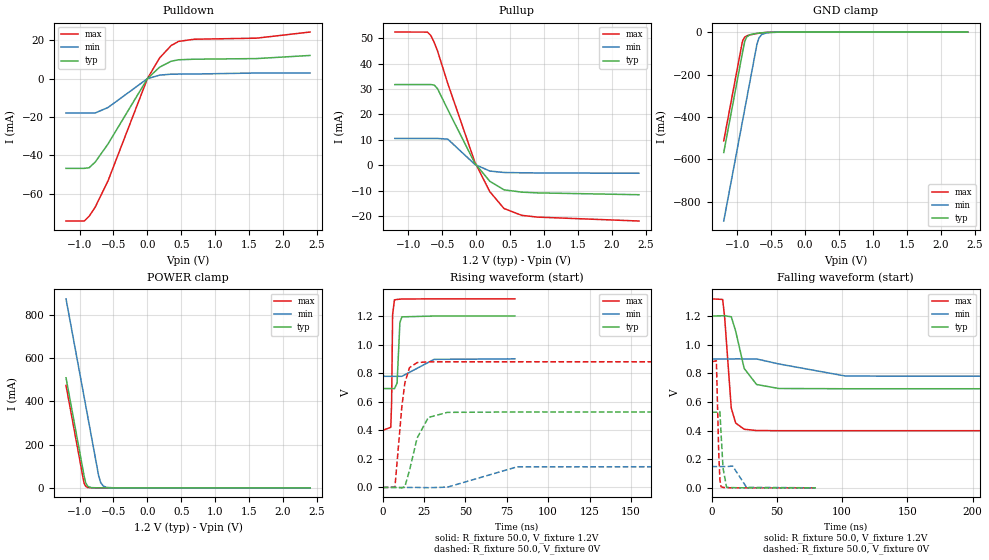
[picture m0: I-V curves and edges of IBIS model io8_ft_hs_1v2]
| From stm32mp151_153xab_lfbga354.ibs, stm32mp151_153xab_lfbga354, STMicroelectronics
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[Model]   io8_ft_hs_1v2
Model_type I/O
Polarity   Non-Inverting
Enable   Active-Low
| CAP_THRESHOLD on pad IOFT is "UDTCAPC" :
| Rising=20.00f vddiom   Falling=80.00f vddiom
| C_comp min and max val. don't necessarily correlate with the min and max pvt
| but are the smallest and greatest pad capacitance found.
| var   typ   min   max
C_comp   3.10955pF  3.08200pF  3.12755pF
|C_comp_pullup   1.83575pF  1.59880pF  1.76540pF
|C_comp_pulldown   1.27380pF  1.48320pF  1.36215pF
Vinl = 360.0mV
Vinh = 792.0mV
Vmeas = 600.0mV   | Reference voltage for timing measurements
Cref  = 50.0pF   | Timing specification test load capacitance value
Rref  = 100.0MOhm   | Timing specification test load resistance value
Vref  = 0V   | Timing specification test load voltage
[Model Spec]
| TIME_THRESHOLD on pin ZIV11 is "CMOS" :
| Rising=40.00f vdd   Falling=60.00f vdd
Vinl 463.60000mV 362.60000mV 506.60000mV
Vinh 741.40000mV 545.40000mV 817.40000mV
| variable   typ   min   max
[Temperature Range] 25.0 140.0 -40.0
| variable   typ   min   max
[Voltage Range] 1.2V 900.0mV 1.32V
| variable   typ   min   max
[POWER Clamp Reference] 1.2V 900.0mV 1.32V
| variable   typ   min   max
[GND Clamp Reference] 0V 0V 0V
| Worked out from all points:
|   slope of the pulldown table from 0 to 0.18 V, typ, clamps not added: 30 ohm
|   slope of the pullup table from 0 to 0.18 V, typ, clamps not added: 31.1 ohm
|   GND clamp passes 1 mA (typ) near -0.52 V on its own axis
|   POWER clamp passes 1 mA (typ) near -0.83 V on its own axis
|   rising waveform, R_fixture 50.0, V_fixture 1.2V: 20-80 % time 986ps typ, 2.99ns min, 510ps max; typ from 0.692 V to 1.2 V
|   falling waveform, R_fixture 50.0, V_fixture 1.2V: 20-80 % time 8.61ns typ, 22.8ns min, 4.22ns max; typ from 1.2 V to 0.692 V
|   rising waveform, R_fixture 50.0, V_fixture 0V: 20-80 % time 7.36ns typ, 17.7ns min, 4.07ns max; typ from 0 V to 0.528 V
|   falling waveform, R_fixture 50.0, V_fixture 0V: 20-80 % time 2.15ns typ, 4.88ns min, 1.52ns max; typ from 0.528 V to 0 V
[POWER Clamp]
-1.2V     508.8mA    874.1mA    473.5mA
-940mV    66.83mA    432.1mA    31.5mA
-930mV    49.83mA    415.1mA    19.15mA
-910mV    22.88mA    381.1mA    7.077mA
-880mV    7.117mA    330.1mA    1.59mA
-830mV    1.017mA    245.1mA    132uA
-720mV    14.05uA    58.12mA    554nA
-690mV    4.373uA    25.03mA    124.7nA
-650mV    922.4nA    8.136mA    17.22nA
-600mV    132.5nA    1.998mA    1.555nA
-490mV    2.763nA    90.9uA     103.5pA
2.4V      0A         0A         0A
[GND Clamp]
-1.2V     -567.2mA   -889.7mA   -512.2mA
-930mV    -108.2mA   -430.7mA   -53.23mA
-920mV    -91.21mA   -413.7mA   -40.49mA
-890mV    -43.51mA   -362.7mA   -23.59mA
-860mV    -22.57mA   -311.7mA   -17.89mA
-810mV    -12.11mA   -226.7mA   -13.23mA
-710mV    -6.053mA   -57.05mA   -7.064mA
-680mV    -4.908mA   -27.37mA   -5.632mA
-640mV    -3.605mA   -11.51mA   -3.985mA
-560mV    -1.665mA   -3.218mA   -1.61mA
-360mV    -34.72uA   -209.4uA   -9.248uA
2.4V      3.381nA    1.198uA    162.5pA
| variable   typ   min   max
[Pullup Reference] 1.2V 900.0mV 1.32V
| variable   typ   min   max
[Pulldown Reference] 0V 0V 0V
[Pullup]
-1.2V     31.77mA    10.56mA    52.45mA
-720mV    31.77mA    10.56mA    52.43mA
-670mV    31.77mA    10.56mA    51.08mA
-620mV    31.6mA     10.56mA    48.4mA
-570mV    30.11mA    10.56mA    44.93mA
-420mV    21.94mA    10.3mA     32.23mA
-20mV     787.9uA    340.3uA    1.238mA
200mV     -6.284mA   -2.265mA   -10.37mA
410mV     -9.651mA   -2.83mA    -17.01mA
670mV     -10.56mA   -2.945mA   -19.69mA
900mV     -10.86mA   -3.008mA   -20.39mA
2.4V      -11.58mA   -3.134mA   -21.93mA
[Pulldown]
-1.2V     -46.7mA    -17.86mA   -74.13mA
-930mV    -46.7mA    -17.86mA   -74.13mA
-860mV    -46.38mA   -17.86mA   -71.67mA
-770mV    -43.45mA   -17.86mA   -66.94mA
-580mV    -33.98mA   -14.99mA   -53.18mA
0V        0A         0A         0A
180mV     6.001mA    1.854mA    10.79mA
350mV     9.086mA    2.357mA    17.24mA
460mV     9.857mA    2.4mA      19.42mA
690mV     10.15mA    2.431mA    20.56mA
1.61V     10.48mA    2.965mA    21.11mA
2.4V      12.11mA    2.965mA    24.31mA
[Ramp]
dV/dt_r 316.99135mV/7.36155ns 89.07848mV/17.68703ns 527.83651mV/4.07371ns
dV/dt_f 304.65901mV/8.60631ns 73.19211mV/22.84083ns 552.4109mV/4.21755ns
R_load = 50.0
| Removed startup time: 0s 0s 0s  .
| Removed end time: 79.9ns.
[Rising Waveform]
R_fixture   = 50.0
V_fixture   = 1.2V
V_fixture_min = 900.0mV
V_fixture_max = 1.32V
0s        692.2mV    778mV      399.3mV
4.9ns     692.2mV    778mV      421.3mV
5.4ns     692.2mV    778mV      597.7mV
6ns       692.3mV    778mV      1.209V
7.1ns     691.4mV    778mV      1.313V
8.7ns     730.5mV    778mV      1.316V
10.4ns    1.154V     778mV      1.318V
11.6ns    1.194V     778mV      1.319V
31.1ns    1.2V       896.5mV    1.32V
79.9ns    1.2V       900mV      1.32V
| Removed startup time: 0s 0s 0s  .
| Removed end time: 399.9ns.
[Falling Waveform]
R_fixture   = 50.0
V_fixture   = 1.2V
V_fixture_min = 900.0mV
V_fixture_max = 1.32V
0s        1.2V       900mV      1.32V
8.5ns     1.202V     900mV      1.316V
10ns      1.202V     900mV      1.196V
15.1ns    1.195V     899.9mV    557.4mV
18.5ns    1.094V     900.9mV    452.4mV
25ns      833.9mV    900.5mV    409.2mV
34.5ns    721.8mV    900.3mV    400.3mV
51.6ns    694mV      865.3mV    399.3mV
102.8ns   692.2mV    780.7mV    399.3mV
399.9ns   692.2mV    778mV      399.3mV
| Removed startup time: 0s 0s 0s  .
| Removed end time: 399.9ns.
[Rising Waveform]
R_fixture   = 50.0
V_fixture   = 0V
V_fixture_min = 0V
V_fixture_max = 0V
0s        50.36nV    1.017uV    135.6nV
7.4ns     94.81uV    1.097uV    2.269mV
11.6ns    -2.749mV   1.095uV    567.9mV
13.4ns    4.819mV    1.094uV    731.4mV
16.2ns    119.7mV    777nV      838.9mV
20.8ns    345.7mV    38.44uV    874.1mV
27.6ns    489.7mV    -1.68mV    879.3mV
39.1ns    525.6mV    2.046mV    879.6mV
81.1ns    528.2mV    143.9mV    879.7mV
399.9ns   528.3mV    148.5mV    879.7mV
| Removed startup time: 0s 0s 0s  .
| Removed end time: 79.9ns.
[Falling Waveform]
R_fixture   = 50.0
V_fixture   = 0V
V_fixture_min = 0V
V_fixture_max = 0V
0s        528.3mV    148.5mV    879.7mV
3.7ns     528.3mV    148.5mV    888mV
5.5ns     529mV      148.5mV    243.5mV
6.4ns     532.7mV    148.5mV    57.34mV
7.2ns     393.4mV    148.5mV    8.398mV
8.8ns     138.8mV    148.5mV    3.209mV
11.5ns    4.073mV    148.5mV    1.141mV
16.2ns    1.329mV    152mV      284.6uV
26.8ns    208.4uV    3.678mV    17.1uV
79.9ns    326.9nV    43.68uV    871.7nV
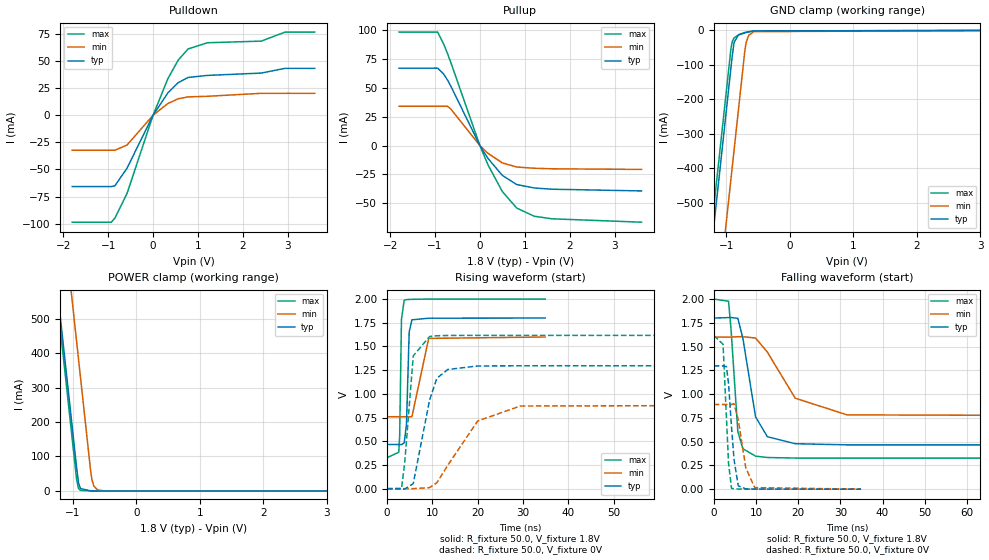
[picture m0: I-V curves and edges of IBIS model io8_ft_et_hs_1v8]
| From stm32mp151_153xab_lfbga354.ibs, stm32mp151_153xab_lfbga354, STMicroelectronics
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[Model]   io8_ft_et_hs_1v8
Model_type I/O
Polarity   Non-Inverting
Enable   Active-Low
| CAP_THRESHOLD on pad IOFT is "UDTCAPC" :
| Rising=20.00f vddiom   Falling=80.00f vddiom
| C_comp min and max val. don't necessarily correlate with the min and max pvt
| but are the smallest and greatest pad capacitance found.
| var   typ   min   max
C_comp   3.43098pF  3.42356pF  3.49925pF
|C_comp_pullup   1.96705pF  2.05925pF  1.91835pF
|C_comp_pulldown   1.46393pF  1.36431pF  1.58090pF
Vinl = 640.0mV
Vinh = 1.2V
Vmeas = 900.0mV   | Reference voltage for timing measurements
Cref  = 50.0pF   | Timing specification test load capacitance value
Rref  = 100.0MOhm   | Timing specification test load resistance value
Vref  = 0V   | Timing specification test load voltage
[Model Spec]
| TIME_THRESHOLD on pin ZIV11 is "CMOS" :
| Rising=40.00f vdd   Falling=60.00f vdd
Vinl 738.60000mV 665.60000mV 824.60000mV
Vinh 1.04640V 924.40000mV 1.13940V
| variable   typ   min   max
[Temperature Range] 25.0 140.0 -40.0
| variable   typ   min   max
[Voltage Range] 1.8V 1.6V 2.0V
| variable   typ   min   max
[POWER Clamp Reference] 1.8V 1.6V 2.0V
| variable   typ   min   max
[GND Clamp Reference] 0V 0V 0V
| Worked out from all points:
|   slope of the pulldown table from 0 to 0.27 V, typ, clamps not added: 16 ohm
|   slope of the pullup table from 0 to 0.27 V, typ, clamps not added: 17 ohm
|   GND clamp passes 1 mA (typ) near -0.52 V on its own axis
|   POWER clamp passes 1 mA (typ) near -0.83 V on its own axis
|   rising waveform, R_fixture 50.0, V_fixture 1.8V: 20-80 % time 437ps typ, 906ps min, 301ps max; typ from 0.466 V to 1.8 V
|   falling waveform, R_fixture 50.0, V_fixture 1.8V: 20-80 % time 2.94ns typ, 7.3ns min, 1.46ns max; typ from 1.8 V to 0.466 V
|   rising waveform, R_fixture 50.0, V_fixture 0V: 20-80 % time 3.11ns typ, 7.36ns min, 1.52ns max; typ from 0 V to 1.3 V
|   falling waveform, R_fixture 50.0, V_fixture 0V: 20-80 % time 1.32ns typ, 2.03ns min, 920ps max; typ from 1.3 V to 0 V
[POWER Clamp]
-1.8V     1.529A     1.894A     1.494A
-940mV    66.83mA    432.1mA    31.5mA
-910mV    22.88mA    381.1mA    7.077mA
-880mV    7.117mA    330.1mA    1.59mA
-720mV    14.05uA    58.12mA    554nA
-700mV    6.453uA    33.14mA    205nA
-670mV    2.008uA    14.27mA    46.29nA
-610mV    195.5nA    2.645mA    2.508nA
-500mV    3.962nA    120.4uA    139.7pA
3.6V      0A         0A         0A
[GND Clamp]
-1.8V     -1.588A    -1.91A     -1.533A
-1.26V    -670.3mA   -992.4mA   -614.9mA
-1.2V     -568.3mA   -890.4mA   -512.9mA
-930mV    -109.3mA   -431.4mA   -53.86mA
-910mV    -75.33mA   -397.4mA   -32.91mA
-880mV    -34.88mA   -346.4mA   -21.56mA
-810mV    -12.56mA   -227.4mA   -13.55mA
-710mV    -6.275mA   -57.63mA   -7.234mA
-690mV    -5.461mA   -35.21mA   -6.234mA
-650mV    -4.039mA   -14.43mA   -4.463mA
-570mV    -1.908mA   -3.832mA   -1.869mA
3.6V      5.084nA    1.599uA    245.6pA
| variable   typ   min   max
[Pullup Reference] 1.8V 1.6V 2.0V
| variable   typ   min   max
[Pulldown Reference] 0V 0V 0V
[Pullup]
-1.8V     67.02mA    34.03mA    98.24mA
-940mV    67.02mA    34.03mA    98.24mA
-810mV    62.07mA    34.03mA    88.1mA
-720mV    56.66mA    34.03mA    79.54mA
-650mV    51.66mA    31.79mA    72.23mA
0V        7.41pA     1.33nA     4.294pA
180mV     -11.09mA   -6.716mA   -16.63mA
500mV     -25.8mA    -15mA      -39.78mA
820mV     -33.72mA   -18.55mA   -54.08mA
1.21V     -36.68mA   -19.61mA   -61.13mA
1.6V      -37.75mA   -20.08mA   -63.35mA
3.6V      -39.24mA   -20.63mA   -66.3mA
[Pulldown]
-1.8V     -65.8mA    -32.31mA   -98.64mA
-930mV    -65.8mA    -32.31mA   -98.64mA
-850mV    -65.04mA   -32.31mA   -94.81mA
-580mV    -48.83mA   -27.49mA   -72.14mA
0V        0A         -3pA       0A
330mV     20.59mA    10.79mA    33.74mA
560mV     30.02mA    15.15mA    50.81mA
780mV     34.81mA    16.9mA     61.1mA
1.21V     36.69mA    17.44mA    66.81mA
2.41V     38.85mA    20.19mA    68.31mA
2.94V     43.21mA    20.19mA    76.64mA
3.6V      43.21mA    20.19mA    76.64mA
[Ramp]
dV/dt_r 777.93018mV/3.10442ns 534.23292mV/7.35934ns 970.1258mV/1.52263ns
dV/dt_f 800.59875mV/2.93456ns 504.72162mV/7.29661ns 1.00395V/1.45577ns
R_load = 50.0
| Removed startup time: 0s 0s 0s  .
| Removed end time: 34.9ns.
[Rising Waveform]
R_fixture   = 50.0
V_fixture   = 1.8V
V_fixture_min = 1.6V
V_fixture_max = 2.0V
0s        465.7mV    758.8mV    326.8mV
2.6ns     465.7mV    758.8mV    384.2mV
2.8ns     465.7mV    758.8mV    552.8mV
3.2ns     464.9mV    758.8mV    1.785V
3.8ns     482.2mV    758.8mV    1.989V
4.3ns     676.5mV    758.8mV    1.994V
4.9ns     1.653V     758.9mV    1.996V
5.5ns     1.781V     758.3mV    1.997V
9.2ns     1.798V     1.585V     2V
34.9ns    1.8V       1.6V       2V
| Removed startup time: 0s 0s 0s  .
| Removed end time: 199.9ns.
[Falling Waveform]
R_fixture   = 50.0
V_fixture   = 1.8V
V_fixture_min = 1.6V
V_fixture_max = 2.0V
0s        1.8V       1.6V       2V
3.5ns     1.805V     1.6V       1.977V
4.1ns     1.806V     1.6V       1.676V
5.7ns     1.797V     1.604V     606.9mV
6.9ns     1.587V     1.604V     425mV
9.9ns     761.1mV    1.59V      347.6mV
12.7ns    551.8mV    1.442V     333.1mV
19.3ns    478.2mV    956.9mV    327.3mV
31.6ns    466.1mV    781.7mV    326.8mV
199.9ns   465.7mV    758.8mV    326.8mV
| Removed startup time: 0s 0s 0s  .
| Removed end time: 199.9ns.
[Rising Waveform]
R_fixture   = 50.0
V_fixture   = 0V
V_fixture_min = 0V
V_fixture_max = 0V
0s        626.1nV    548.5nV    -418.8nV
3.2ns     194.9uV    667.5nV    1.079mV
3.9ns     -5.268mV   816.8nV    266.4mV
5.8ns     53.91mV    103.4uV    1.401V
9.4ns     935.7mV    10.76mV    1.605V
11ns      1.164V     62.56mV    1.613V
13.4ns    1.257V     246.3mV    1.616V
20ns      1.294V     713.8mV    1.617V
29.4ns    1.296V     871.9mV    1.617V
199.9ns   1.297V     890.4mV    1.617V
| Removed startup time: 0s 0s 0s  .
| Removed end time: 34.9ns.
[Falling Waveform]
R_fixture   = 50.0
V_fixture   = 0V
V_fixture_min = 0V
V_fixture_max = 0V
0s        1.297V     890.4mV    1.617V
2.2ns     1.297V     890.4mV    1.524V
3ns       1.29V      890.4mV    755mV
3.5ns     1.109V     890.5mV    272.6mV
4.2ns     655.1mV    890.2mV    9.557mV
4.8ns     312mV      899.7mV    3.295mV
5.8ns     35.07mV    730.6mV    1.496mV
7.6ns     2.478mV    222mV      713.6uV
9.7ns     1.069mV    16.4mV     328uV
34.9ns    -58.81nV   40.43uV    -141nV
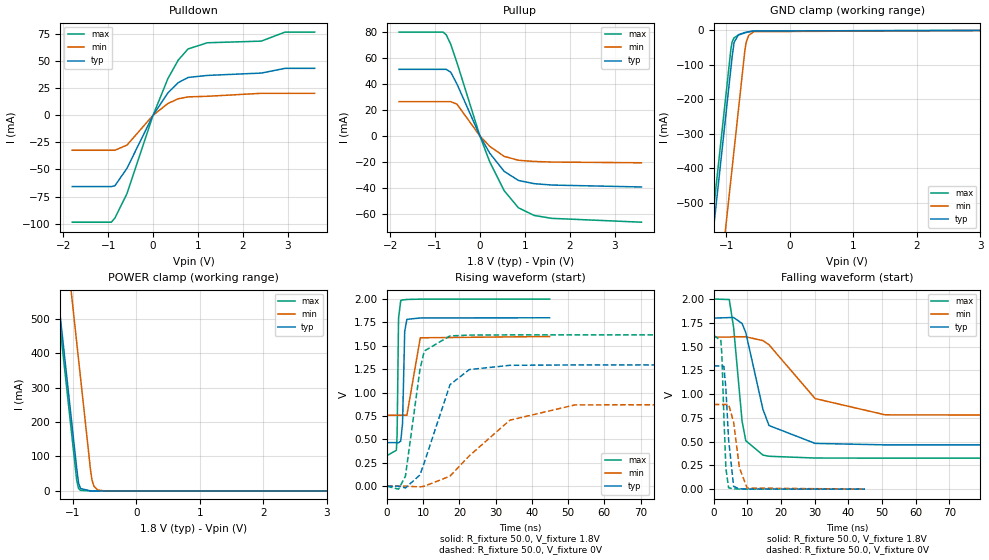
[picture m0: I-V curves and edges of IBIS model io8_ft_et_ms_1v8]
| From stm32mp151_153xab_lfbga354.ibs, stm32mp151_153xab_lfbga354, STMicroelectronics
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[Model]   io8_ft_et_ms_1v8
Model_type I/O
Polarity   Non-Inverting
Enable   Active-Low
| CAP_THRESHOLD on pad IOFT is "UDTCAPC" :
| Rising=20.00f vddiom   Falling=80.00f vddiom
| C_comp min and max val. don't necessarily correlate with the min and max pvt
| but are the smallest and greatest pad capacitance found.
| var   typ   min   max
C_comp   3.43098pF  3.42356pF  3.49925pF
|C_comp_pullup   1.96705pF  2.05925pF  1.91840pF
|C_comp_pulldown   1.46393pF  1.36431pF  1.58085pF
Vinl = 640.0mV
Vinh = 1.2V
Vmeas = 900.0mV   | Reference voltage for timing measurements
Cref  = 50.0pF   | Timing specification test load capacitance value
Rref  = 100.0MOhm   | Timing specification test load resistance value
Vref  = 0V   | Timing specification test load voltage
[Model Spec]
| TIME_THRESHOLD on pin ZIV11 is "CMOS" :
| Rising=40.00f vdd   Falling=60.00f vdd
Vinl 738.60000mV 665.60000mV 824.60000mV
Vinh 1.04640V 924.40000mV 1.13940V
| variable   typ   min   max
[Temperature Range] 25.0 140.0 -40.0
| variable   typ   min   max
[Voltage Range] 1.8V 1.6V 2.0V
| variable   typ   min   max
[POWER Clamp Reference] 1.8V 1.6V 2.0V
| variable   typ   min   max
[GND Clamp Reference] 0V 0V 0V
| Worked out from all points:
|   slope of the pulldown table from 0 to 0.27 V, typ, clamps not added: 16 ohm
|   slope of the pullup table from 0 to 0.27 V, typ, clamps not added: 17 ohm
|   GND clamp passes 1 mA (typ) near -0.52 V on its own axis
|   POWER clamp passes 1 mA (typ) near -0.83 V on its own axis
|   rising waveform, R_fixture 50.0, V_fixture 1.8V: 20-80 % time 431ps typ, 900ps min, 295ps max; typ from 0.466 V to 1.8 V
|   falling waveform, R_fixture 50.0, V_fixture 1.8V: 20-80 % time 5.09ns typ, 12.6ns min, 2.6ns max; typ from 1.8 V to 0.466 V
|   rising waveform, R_fixture 50.0, V_fixture 0V: 20-80 % time 6.39ns typ, 14.9ns min, 3.24ns max; typ from 0 V to 1.3 V
|   falling waveform, R_fixture 50.0, V_fixture 0V: 20-80 % time 1.34ns typ, 2.05ns min, 933ps max; typ from 1.3 V to 0 V
[POWER Clamp]
-1.8V     1.529A     1.894A     1.494A
-940mV    66.83mA    432.1mA    31.5mA
-910mV    22.88mA    381.1mA    7.077mA
-880mV    7.117mA    330.1mA    1.59mA
-720mV    14.05uA    58.12mA    554nA
-700mV    6.453uA    33.14mA    205nA
-670mV    2.008uA    14.27mA    46.29nA
-610mV    195.5nA    2.645mA    2.508nA
-500mV    3.962nA    120.4uA    139.7pA
3.6V      0A         0A         0A
[GND Clamp]
-1.8V     -1.588A    -1.91A     -1.533A
-1.26V    -670.3mA   -992.4mA   -614.9mA
-1.2V     -568.3mA   -890.4mA   -512.9mA
-930mV    -109.3mA   -431.4mA   -53.86mA
-910mV    -75.33mA   -397.4mA   -32.91mA
-880mV    -34.88mA   -346.4mA   -21.56mA
-810mV    -12.56mA   -227.4mA   -13.55mA
-710mV    -6.275mA   -57.63mA   -7.234mA
-690mV    -5.461mA   -35.21mA   -6.234mA
-650mV    -4.039mA   -14.43mA   -4.463mA
-570mV    -1.908mA   -3.832mA   -1.869mA
3.6V      5.084nA    1.599uA    245.6pA
| variable   typ   min   max
[Pullup Reference] 1.8V 1.6V 2.0V
| variable   typ   min   max
[Pulldown Reference] 0V 0V 0V
[Pullup]
-1.8V     51.18mA    26.38mA    79.82mA
-820mV    51.18mA    26.38mA    79.82mA
-750mV    51.18mA    26.38mA    77.72mA
-650mV    49.01mA    26.38mA    70.5mA
-510mV    39.89mA    24.38mA    56.25mA
0V        7.41pA     1.33nA     4.294pA
220mV     -13.28mA   -8.011mA   -19.99mA
540mV     -27.17mA   -15.7mA    -42.05mA
860mV     -34.25mA   -18.73mA   -55.26mA
1.21V     -36.68mA   -19.61mA   -61.13mA
1.6V      -37.75mA   -20.08mA   -63.35mA
3.6V      -39.24mA   -20.63mA   -66.3mA
[Pulldown]
-1.8V     -65.8mA    -32.31mA   -98.64mA
-930mV    -65.8mA    -32.31mA   -98.64mA
-850mV    -65.04mA   -32.31mA   -94.81mA
-580mV    -48.83mA   -27.49mA   -72.14mA
0V        0A         -3pA       0A
330mV     20.59mA    10.79mA    33.74mA
560mV     30.02mA    15.15mA    50.81mA
780mV     34.81mA    16.9mA     61.1mA
1.21V     36.69mA    17.44mA    66.81mA
2.41V     38.85mA    20.19mA    68.31mA
2.94V     43.21mA    20.19mA    76.64mA
3.6V      43.21mA    20.19mA    76.64mA
[Ramp]
dV/dt_r 777.92839mV/6.38479ns 534.22846mV/14.94528ns 970.12895mV/3.24087ns
dV/dt_f 800.59801mV/5.08757ns 504.71984mV/12.61846ns 1.00395V/2.59515ns
R_load = 50.0
| Removed startup time: 0s 0s 0s  .
| Removed end time: 44.9ns.
[Rising Waveform]
R_fixture   = 50.0
V_fixture   = 1.8V
V_fixture_min = 1.6V
V_fixture_max = 2.0V
0s        465.7mV    758.8mV    326.8mV
2.6ns     465.7mV    758.8mV    384.2mV
2.8ns     465.7mV    758.8mV    551.6mV
3.2ns     464.8mV    758.8mV    1.796V
3.8ns     482.3mV    758.8mV    1.984V
4.3ns     672.9mV    758.8mV    1.991V
4.9ns     1.657V     758.9mV    1.993V
5.5ns     1.783V     758.3mV    1.996V
9.2ns     1.798V     1.586V     1.999V
44.9ns    1.8V       1.6V       2V
| Removed startup time: 0s 0s 0s  .
| Removed end time: 379.9ns.
[Falling Waveform]
R_fixture   = 50.0
V_fixture   = 1.8V
V_fixture_min = 1.6V
V_fixture_max = 2.0V
0s        1.8V       1.6V       2V
4.6ns     1.805V     1.6V       1.995V
5.9ns     1.806V     1.604V     1.698V
8.4ns     1.743V     1.603V     716.9mV
9.5ns     1.649V     1.603V     510.5mV
14.6ns    839.5mV    1.563V     358.5mV
16.4ns    669.7mV    1.519V     346.1mV
30.1ns    481.4mV    953.1mV    327.5mV
50.9ns    466.1mV    782mV      326.7mV
379.9ns   465.7mV    758.8mV    326.8mV
| Removed startup time: 0s 0s 0s  .
| Removed end time: 379.9ns.
[Rising Waveform]
R_fixture   = 50.0
V_fixture   = 0V
V_fixture_min = 0V
V_fixture_max = 0V
0s        675nV      583.3nV    -420.7nV
3.2ns     221.5uV    669.6nV    -31.72mV
5.1ns     -18.82mV   26.91uV    108mV
9.1ns     120mV      -7.652mV   1.247V
10.3ns    252.1mV    -382.1uV   1.445V
17.4ns    1.085V     107.4mV    1.606V
22.7ns    1.246V     324mV      1.615V
33.9ns    1.292V     705.3mV    1.617V
51.9ns    1.296V     869mV      1.617V
379.9ns   1.297V     890.4mV    1.617V
| Removed startup time: 0s 0s 0s  .
| Removed end time: 44.9ns.
[Falling Waveform]
R_fixture   = 50.0
V_fixture   = 0V
V_fixture_min = 0V
V_fixture_max = 0V
0s        1.297V     890.4mV    1.617V
2.1ns     1.297V     890.4mV    1.564V
2.4ns     1.296V     890.4mV    1.416V
3ns       1.291V     890.4mV    766.9mV
3.6ns     1.055V     890.5mV    218.5mV
4.4ns     522.8mV    891.6mV    14.95mV
5.9ns     28.25mV    704mV      3.538mV
7.6ns     3.614mV    227.1mV    1.353mV
9.9ns     1.893mV    11.93mV    638.1uV
44.9ns    5.087uV    72.19uV    -911.7nV
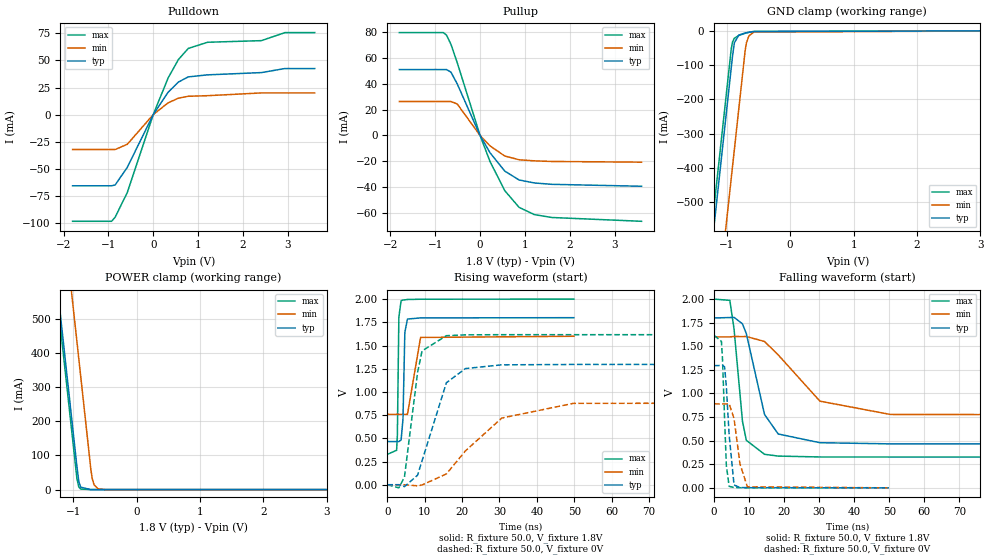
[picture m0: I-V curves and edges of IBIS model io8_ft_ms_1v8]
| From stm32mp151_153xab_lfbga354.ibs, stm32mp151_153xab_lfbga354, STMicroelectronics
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[Model]   io8_ft_ms_1v8
Model_type I/O
Polarity   Non-Inverting
Enable   Active-Low
| CAP_THRESHOLD on pad IOFT is "UDTCAPC" :
| Rising=20.00f vddiom   Falling=80.00f vddiom
| C_comp min and max val. don't necessarily correlate with the min and max pvt
| but are the smallest and greatest pad capacitance found.
| var   typ   min   max
C_comp   3.43308pF  3.42731pF  3.49995pF
|C_comp_pullup   1.98355pF  2.07755pF  1.93335pF
|C_comp_pulldown   1.44953pF  1.34976pF  1.56660pF
Vinl = 640.0mV
Vinh = 1.2V
Vmeas = 900.0mV   | Reference voltage for timing measurements
Cref  = 50.0pF   | Timing specification test load capacitance value
Rref  = 100.0MOhm   | Timing specification test load resistance value
Vref  = 0V   | Timing specification test load voltage
[Model Spec]
| TIME_THRESHOLD on pin ZIV11 is "CMOS" :
| Rising=40.00f vdd   Falling=60.00f vdd
Vinl 738.60000mV 665.60000mV 824.60000mV
Vinh 1.04640V 924.40000mV 1.13940V
| variable   typ   min   max
[Temperature Range] 25.0 140.0 -40.0
| variable   typ   min   max
[Voltage Range] 1.8V 1.6V 2.0V
| variable   typ   min   max
[POWER Clamp Reference] 1.8V 1.6V 2.0V
| variable   typ   min   max
[GND Clamp Reference] 0V 0V 0V
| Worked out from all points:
|   slope of the pulldown table from 0 to 0.27 V, typ, clamps not added: 16 ohm
|   slope of the pullup table from 0 to 0.27 V, typ, clamps not added: 17 ohm
|   GND clamp passes 1 mA (typ) near -0.52 V on its own axis
|   POWER clamp passes 1 mA (typ) near -0.83 V on its own axis
|   rising waveform, R_fixture 50.0, V_fixture 1.8V: 20-80 % time 388ps typ, 810ps min, 280ps max; typ from 0.466 V to 1.8 V
|   falling waveform, R_fixture 50.0, V_fixture 1.8V: 20-80 % time 4.86ns typ, 12ns min, 2.5ns max; typ from 1.8 V to 0.466 V
|   rising waveform, R_fixture 50.0, V_fixture 0V: 20-80 % time 5.71ns typ, 13.2ns min, 2.89ns max; typ from 0 V to 1.3 V
|   falling waveform, R_fixture 50.0, V_fixture 0V: 20-80 % time 1.33ns typ, 2.04ns min, 930ps max; typ from 1.3 V to 0 V
[POWER Clamp]
-1.8V     1.529A     1.894A     1.494A
-940mV    66.83mA    432.1mA    31.5mA
-910mV    22.88mA    381.1mA    7.077mA
-880mV    7.117mA    330.1mA    1.59mA
-720mV    14.05uA    58.12mA    554nA
-700mV    6.453uA    33.14mA    205nA
-670mV    2.008uA    14.27mA    46.28nA
-610mV    195.3nA    2.645mA    2.497nA
-500mV    3.855nA    120.4uA    130.5pA
3.6V      0A         0A         0A
[GND Clamp]
-1.8V     -1.588A    -1.91A     -1.533A
-1.26V    -670.3mA   -992.4mA   -614.9mA
-1.2V     -568.3mA   -890.4mA   -512.9mA
-930mV    -109.3mA   -431.4mA   -53.86mA
-910mV    -75.33mA   -397.4mA   -32.91mA
-880mV    -34.88mA   -346.4mA   -21.56mA
-810mV    -12.56mA   -227.4mA   -13.55mA
-710mV    -6.275mA   -57.63mA   -7.234mA
-690mV    -5.461mA   -35.21mA   -6.234mA
-650mV    -4.039mA   -14.43mA   -4.463mA
-570mV    -1.908mA   -3.832mA   -1.869mA
3.6V      5.036nA    1.588uA    245.5pA
| variable   typ   min   max
[Pullup Reference] 1.8V 1.6V 2.0V
| variable   typ   min   max
[Pulldown Reference] 0V 0V 0V
[Pullup]
-1.8V     50.91mA    26.21mA    79.43mA
-820mV    50.91mA    26.21mA    79.43mA
-750mV    50.91mA    26.21mA    77.51mA
-650mV    48.89mA    26.21mA    70.41mA
-510mV    39.85mA    24.32mA    56.22mA
0V        7.41pA     1.33nA     4.294pA
220mV     -13.28mA   -8.005mA   -19.98mA
550mV     -27.48mA   -15.85mA   -42.58mA
870mV     -34.35mA   -18.76mA   -55.49mA
1.21V     -36.65mA   -19.59mA   -61.09mA
1.6V      -37.71mA   -20.06mA   -63.31mA
3.6V      -39.21mA   -20.61mA   -66.25mA
[Pulldown]
-1.8V     -65.8mA    -32.31mA   -98.64mA
-930mV    -65.8mA    -32.31mA   -98.64mA
-850mV    -65.04mA   -32.31mA   -94.81mA
-580mV    -48.83mA   -27.49mA   -72.14mA
0V        0A         0A         0A
330mV     20.59mA    10.79mA    33.74mA
560mV     30.02mA    15.15mA    50.81mA
780mV     34.81mA    16.9mA     61.1mA
1.21V     36.69mA    17.44mA    66.81mA
2.41V     38.78mA    19.98mA    68.31mA
2.94V     42.55mA    19.98mA    75.77mA
3.6V      42.55mA    19.98mA    75.77mA
[Ramp]
dV/dt_r 777.75128mV/5.71241ns 533.93294mV/13.17985ns 970.01765mV/2.89089ns
dV/dt_f 800.5979mV/4.85474ns 504.72167mV/11.97048ns 1.00395V/2.49867ns
R_load = 50.0
| Removed startup time: 0s 0s 0s  .
| Removed end time: 49.9ns.
[Rising Waveform]
R_fixture   = 50.0
V_fixture   = 1.8V
V_fixture_min = 1.6V
V_fixture_max = 2.0V
0s        465.7mV    758.8mV    326.8mV
2.5ns     465.7mV    758.8mV    371.4mV
2.7ns     465.7mV    758.8mV    527.8mV
3.1ns     464.8mV    758.8mV    1.806V
3.7ns     483.2mV    758.8mV    1.983V
4.2ns     706.2mV    758.8mV    1.99V
4.7ns     1.642V     758.9mV    1.992V
5.4ns     1.785V     757.8mV    1.996V
8.9ns     1.798V     1.587V     1.999V
49.9ns    1.8V       1.6V       2V
| Removed startup time: 0s 0s 0s  .
| Removed end time: 499.9ns.
[Falling Waveform]
R_fixture   = 50.0
V_fixture   = 1.8V
V_fixture_min = 1.6V
V_fixture_max = 2.0V
0s        1.8V       1.6V       2V
4.5ns     1.805V     1.6V       1.987V
5.7ns     1.807V     1.604V     1.683V
8.1ns     1.738V     1.603V     706.1mV
9.2ns     1.635V     1.604V     503.8mV
14.4ns    777.2mV    1.551V     355.4mV
18.3ns    570.8mV    1.409V     336.8mV
30.2ns    478.5mV    918.7mV    327.3mV
50.3ns    466.1mV    777.9mV    326.7mV
499.9ns   465.7mV    758.8mV    326.8mV
| Removed startup time: 0s 0s 0s  .
| Removed end time: 499.9ns.
[Rising Waveform]
R_fixture   = 50.0
V_fixture   = 0V
V_fixture_min = 0V
V_fixture_max = 0V
0s        70.95nV    639.7nV    99.6nV
3.1ns     230.6uV    665.7nV    -33.59mV
4.6ns     -20.47mV   -3.222uV   83.93mV
8.1ns     103mV      -11.82mV   1.209V
9.3ns     257.8mV    -2.696mV   1.442V
15.8ns    1.099V     116.6mV    1.606V
20.9ns    1.252V     364.6mV    1.615V
30.6ns    1.292V     718.6mV    1.617V
49.8ns    1.296V     877.1mV    1.617V
499.9ns   1.296V     889.9mV    1.617V
| Removed startup time: 0s 0s 0s  .
| Removed end time: 49.9ns.
[Falling Waveform]
R_fixture   = 50.0
V_fixture   = 0V
V_fixture_min = 0V
V_fixture_max = 0V
0s        1.296V     889.9mV    1.617V
2.1ns     1.296V     889.9mV    1.552V
2.4ns     1.296V     889.9mV    1.365V
3ns       1.284V     889.9mV    734.8mV
3.5ns     1.073V     889.9mV    236.9mV
4.3ns     559.4mV    890.5mV    16.23mV
5.7ns     30.27mV    734.1mV    3.748mV
7.4ns     3.934mV    251.3mV    1.339mV
9.5ns     2.014mV    11.3mV     676.5uV
49.9ns    955.3nV    36.71uV    -1.633uV
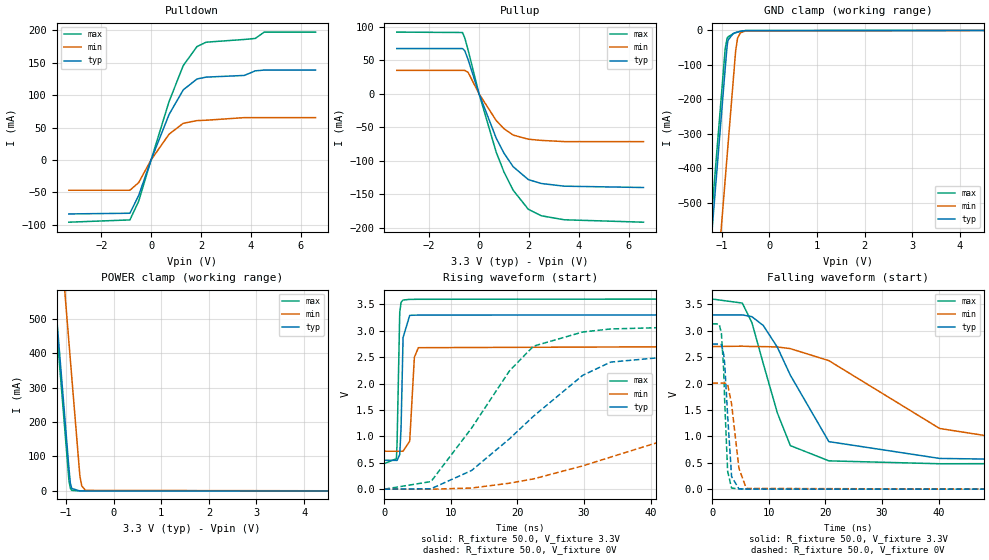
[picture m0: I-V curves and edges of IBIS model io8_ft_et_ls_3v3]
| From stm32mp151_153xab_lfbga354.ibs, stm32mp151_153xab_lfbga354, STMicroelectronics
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[Model]   io8_ft_et_ls_3v3
Model_type I/O
Polarity   Non-Inverting
Enable   Active-Low
| CAP_THRESHOLD on pad IOFT is "UDTCAPC" :
| Rising=20.00f vddiom   Falling=80.00f vddiom
| C_comp min and max val. don't necessarily correlate with the min and max pvt
| but are the smallest and greatest pad capacitance found.
| var   typ   min   max
C_comp   3.68632pF  3.64973pF  3.70805pF
|C_comp_pullup   2.21620pF  2.27950pF  2.11835pF
|C_comp_pulldown   1.47012pF  1.37023pF  1.58970pF
Vinl = 1.08V
Vinh = 2.16V
Vmeas = 1.65V   | Reference voltage for timing measurements
Cref  = 50.0pF   | Timing specification test load capacitance value
Rref  = 100.0MOhm   | Timing specification test load resistance value
Vref  = 0V   | Timing specification test load voltage
[Model Spec]
| TIME_THRESHOLD on pin ZIV11 is "CMOS" :
| Rising=40.00f vdd   Falling=60.00f vdd
Vinl 1.36060V 1.12960V 1.47360V
Vinh 1.71540V 1.45040V 1.82940V
| variable   typ   min   max
[Temperature Range] 25.0 140.0 -40.0
| variable   typ   min   max
[Voltage Range] 3.3V 2.7V 3.6V
| variable   typ   min   max
[POWER Clamp Reference] 3.3V 2.7V 3.6V
| variable   typ   min   max
[GND Clamp Reference] 0V 0V 0V
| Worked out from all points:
|   slope of the pulldown table from 0 to 0.495 V, typ, clamps not added: 9.86 ohm
|   slope of the pullup table from 0 to 0.495 V, typ, clamps not added: 9.93 ohm
|   GND clamp passes 1 mA (typ) near -0.52 V on its own axis
|   POWER clamp passes 1 mA (typ) near -0.83 V on its own axis
|   rising waveform, R_fixture 50.0, V_fixture 3.3V: 20-80 % time 293ps typ, 424ps min, 259ps max; typ from 0.547 V to 3.3 V
|   falling waveform, R_fixture 50.0, V_fixture 3.3V: 20-80 % time 7.79ns typ, 18.1ns min, 5.08ns max; typ from 3.3 V to 0.547 V
|   rising waveform, R_fixture 50.0, V_fixture 0V: 20-80 % time 15.2ns typ, 30.3ns min, 10.2ns max; typ from 0 V to 2.75 V
|   falling waveform, R_fixture 50.0, V_fixture 0V: 20-80 % time 842ps typ, 1.28ns min, 661ps max; typ from 2.75 V to 0 V
[POWER Clamp]
-3.3V     4.079A     4.444A     4.043A
-1.46V    950.8mA    1.316A     915.5mA
-1.28V    644.8mA    1.01A      609.5mA
-1.09V    321.8mA    687.1mA    286.5mA
-1.07V    287.8mA    653.1mA    252.5mA
-940mV    66.83mA    432.1mA    31.5mA
-910mV    22.88mA    381.1mA    7.077mA
-880mV    7.117mA    330.1mA    1.59mA
-710mV    9.525uA    43.89mA    337.5nA
-670mV    2.01uA     14.27mA    46.78nA
-590mV    92.49nA    1.508mA    1.503nA
6.6V      0A         0A         0A
[GND Clamp]
-3.3V     -4.139A    -4.461A    -4.081A
-1.26V    -670.8mA   -992.8mA   -613.3mA
-1.1V     -398.8mA   -720.8mA   -341.3mA
-930mV    -109.8mA   -431.8mA   -52.32mA
-890mV    -44.91mA   -363.8mA   -23.04mA
-870mV    -28.43mA   -329.8mA   -18.86mA
-760mV    -8.879mA   -142.8mA   -9.749mA
-710mV    -6.383mA   -58.04mA   -7.036mA
-670mV    -4.798mA   -22.41mA   -5.193mA
-610mV    -2.902mA   -7.057mA   -2.962mA
-500mV    -778.4uA   -1.643mA   -611.3uA
6.6V      9.268nA    3.087uA    468pA
| variable   typ   min   max
[Pullup Reference] 3.3V 2.7V 3.6V
| variable   typ   min   max
[Pulldown Reference] 0V 0V 0V
[Pullup]
-3.3V     67.44mA    34.84mA    92.07mA
-660mV    67.44mA    34.84mA    91.43mA
-570mV    64.05mA    34.84mA    83.19mA
-440mV    51.19mA    32.03mA    65.52mA
0V        11.24pA    1.438nA    7.78pA
690mV     -66.39mA   -40.05mA   -87.4mA
1V        -88.71mA   -52.23mA   -116.8mA
1.37V     -109mA     -61.77mA   -144.2mA
1.98V     -128.3mA   -67.94mA   -172.7mA
2.5V      -134.1mA   -69.74mA   -182.3mA
3.42V     -138.1mA   -71.49mA   -188.3mA
6.6V      -140.1mA   -71.49mA   -191.9mA
[Pulldown]
-3.3V     -83.56mA   -46.9mA    -96.31mA
-850mV    -82.46mA   -46.9mA    -92.78mA
-500mV    -55.19mA   -35.23mA   -63.97mA
0V        30fA       -2pA       200fA
720mV     70.07mA    39.69mA    90.11mA
1.29V     108.2mA    56.55mA    145.7mA
1.84V     125mA      60.7mA     175.1mA
2.21V     127.9mA    61.29mA    181.9mA
3.74V     130.5mA    65.29mA    186.1mA
4.18V     137.6mA    65.29mA    187.7mA
4.54V     138.8mA    65.29mA    197.5mA
6.6V      138.8mA    65.29mA    197.5mA
[Ramp]
dV/dt_r 1.64856V/15.21261ns 1.20469V/30.31499ns 1.87853V/10.20233ns
dV/dt_f 1.65162V/7.78511ns 1.18896V/18.06869ns 1.8682V/5.08166ns
R_load = 50.0
| Removed startup time: 0s 0s 0s  .
| Removed end time: 50.9ns.
[Rising Waveform]
R_fixture   = 50.0
V_fixture   = 3.3V
V_fixture_min = 2.7V
V_fixture_max = 3.6V
0s        547.3mV    718.4mV    486.3mV
1.8ns     544.7mV    718.4mV    577mV
1.9ns     544mV      718.4mV    873.8mV
2.3ns     654.7mV    718.4mV    3.35V
2.5ns     1.166V     718.5mV    3.538V
2.8ns     2.871V     717.9mV    3.582V
3.8ns     3.291V     909.8mV    3.594V
4.5ns     3.295V     2.498V     3.595V
5.1ns     3.296V     2.679V     3.596V
50.9ns    3.3V       2.7V       3.6V
| Removed startup time: 0s 0s 0s  .
| Removed end time: 299.9ns.
[Falling Waveform]
R_fixture   = 50.0
V_fixture   = 3.3V
V_fixture_min = 2.7V
V_fixture_max = 3.6V
0s        3.3V       2.7V       3.6V
5.3ns     3.3V       2.708V     3.524V
7ns       3.266V     2.701V     3.152V
9ns       3.1V       2.7V       2.379V
11.5ns    2.687V     2.693V     1.443V
13.8ns    2.157V     2.661V     825.1mV
20.6ns    900.4mV    2.434V     536.1mV
40.2ns    582.1mV    1.149V     481.2mV
58.4ns    555.4mV    846.4mV    484.5mV
299.9ns   547.3mV    718.4mV    486.3mV
| Removed startup time: 0s 0s 0s  .
| Removed end time: 299.9ns.
[Rising Waveform]
R_fixture   = 50.0
V_fixture   = 0V
V_fixture_min = 0V
V_fixture_max = 0V
0s        616.4nV    463.1nV    -459.2nV
7ns       7.244mV    -389.9uV   143.5mV
13.1ns    353.2mV    20.65mV    1.156V
18.8ns    953.5mV    112.9mV    2.241V
22.4ns    1.38V      194.1mV    2.708V
29.8ns    2.155V     440.1mV    2.976V
34ns      2.406V     606.7mV    3.034V
60.5ns    2.709V     1.643V     3.123V
85.3ns    2.74V      1.912V     3.13V
299.9ns   2.748V     2.008V     3.131V
| Removed startup time: 0s 0s 0s  .
| Removed end time: 50.9ns.
[Falling Waveform]
R_fixture   = 50.0
V_fixture   = 0V
V_fixture_min = 0V
V_fixture_max = 0V
0s        2.748V     2.008V     3.131V
1.2ns     2.747V     2.008V     3.128V
1.6ns     2.737V     2.008V     2.953V
2ns       2.556V     2.008V     2.262V
2.2ns     2.351V     2.009V     1.614V
2.7ns     1.394V     1.982V     340.2mV
3.4ns     239.1mV    1.612V     20.03mV
4.7ns     4.957mV    395.1mV    4.603mV
6ns       3.03mV     14.28mV    3.966mV
50.9ns    74.62uV    164.9uV    37.47uV
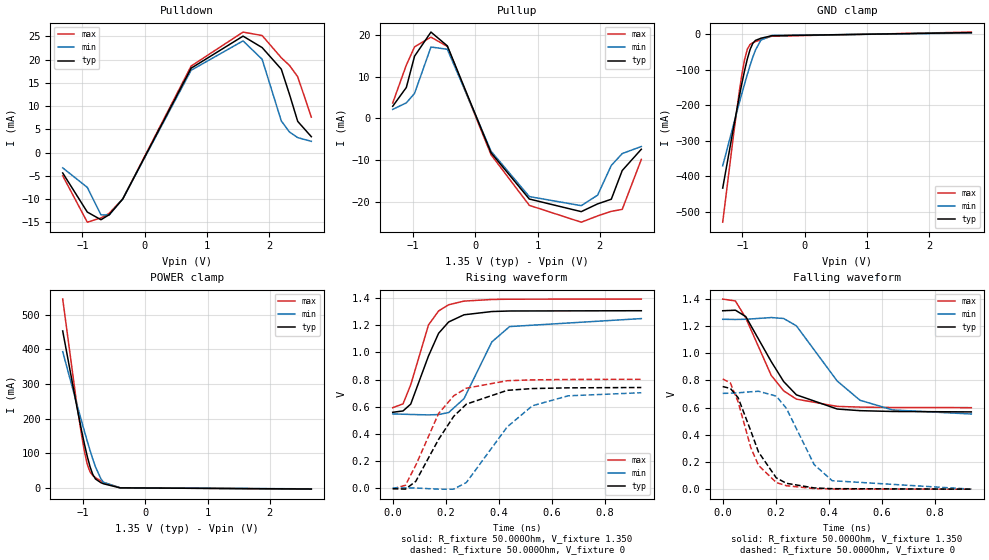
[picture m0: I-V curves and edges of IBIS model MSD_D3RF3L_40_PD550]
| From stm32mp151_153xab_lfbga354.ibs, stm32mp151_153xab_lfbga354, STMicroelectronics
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[Model] MSD_D3RF3L_40_PD550
Model_type   I/O
C_comp 2.422pF   2.338pF   2.546pF
Vinh = 810.000mV
Vinl = 540.000mV
Vmeas = 675.000mV
Vref = 675.000mV
[Model Spec]
Vinh   810.000mV   777.000mV   860.000mV
Vinl   540.000mV   507.000mV   590.000mV
Vmeas   675.000mV   642.000mV   725.000mV
Vref   675.000mV   642.000mV   725.000mV
[Temperature Range]   25.000   125.000   -40.000
[Voltage Range]   1.350V   1.283V   1.450V
[GND Clamp Reference]   0.00V   0.00V   0.00V
[Pulldown Reference]   0.00V   0.00V   0.00V
[POWER Clamp Reference]   1.350V   1.283V   1.450V
[Pullup Reference]   1.350V   1.283V   1.450V
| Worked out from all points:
|   slope of the pulldown table from 0 to 0.203 V, typ, clamps not added: 35.6 ohm
|   slope of the pullup table from 0 to 0.203 V, typ, clamps not added: 29.7 ohm
|   GND clamp passes 1 mA (typ) near -0.40 V on its own axis
|   POWER clamp passes 1 mA (typ) near -0.41 V on its own axis
|   rising waveform, R_fixture 50.000Ohm, V_fixture 1.350: 20-80 % time 89.4ps typ, 110ps min, 77ps max; typ from 0.559 V to 1.31 V
|   rising waveform, R_fixture 50.000Ohm, V_fixture 0: 20-80 % time 143ps typ, 168ps min, 124ps max; typ from -0.005 V to 0.742 V
|   falling waveform, R_fixture 50.000Ohm, V_fixture 1.350: 20-80 % time 142ps typ, 170ps min, 120ps max; typ from 1.31 V to 0.568 V
|   falling waveform, R_fixture 50.000Ohm, V_fixture 0: 20-80 % time 94.9ps typ, 112ps min, 81.9ps max; typ from 0.755 V to 0 V
[GND Clamp]
-1.318V   -433.7mA   -371mA     -529.9mA
-1.142V   -261.3mA   -253.3mA   -281.1mA
-1.055V   -178.8mA   -195.8mA   -166mA
-1.011V   -139.6mA   -167.6mA   -114.8mA
-966.7mV  -102.8mA   -140.2mA   -71.91mA
-922.7mV  -69.98mA   -113.5mA   -42.24mA
-878.8mV  -43.33mA   -88.28mA   -28.82mA
-834.9mV  -25.71mA   -64.84mA   -23.86mA
-790.9mV  -17.19mA   -44.16mA   -20.64mA
-703mV    -11.03mA   -16.2mA    -14.94mA
-527.3mV  -4.003mA   -3.392mA   -5.338mA
2.68V     4.841mA    3.764mA    6.269mA
[Power Clamp]
-1.33V    452.9mA    393.3mA    544.8mA
-1.111V   242.4mA    247.7mA    251.5mA
-1.023V   162.7mA    190.7mA    148.6mA
-978.8mV  125.6mA    162.7mA    104mA
-934.9mV  91.47mA    135.5mA    68.54mA
-890.9mV  62.09mA    109.1mA    46.9mA
-847mV    39.75mA    84.16mA    36.4mA
-803mV    26.39mA    61.34mA    30.3mA
-715.1mV  15.71mA    26.57mA    20.81mA
-671.2mV  12.48mA    16.48mA    16.64mA
-407.6mV  908uA      1.189mA    1.109mA
2.668V    -2.431mA   -2.026mA   -2.89mA
[Pulldown]
-1.318V   -4.4mA     -3.3mA     -5mA
-922.7mV  -12.81mA   -7.5mA     -14.99mA
-703mV    -14.46mA   -13.41mA   -14.07mA
-571.2mV  -13.39mA   -13.44mA   -13.08mA
-351.5mV  -9.985mA   -9.964mA   -9.957mA
747mV     18.13mA    17.69mA    18.59mA
1.582V    25.03mA    24.01mA    25.9mA
1.889V    22.57mA    20.05mA    25.16mA
2.197V    17.93mA    6.8mA      20.38mA
2.329V    12.5mA     4.4mA      18.73mA
2.461V    6.7mA      3.2mA      16.3mA
2.68V     3.4mA      2.4mA      7.6mA
[Pullup]
-1.33V    2.9mA      2.152mA    3.679mA
-1.111V   7.4mA      3.715mA    12.77mA
-978.8mV  14.9mA     5.977mA    17.14mA
-715.1mV  20.68mA    17.1mA     19.47mA
-451.5mV  17.37mA    16.56mA    17.24mA
251.5mV   -8.249mA   -7.869mA   -8.718mA
866.7mV   -19.34mA   -18.75mA   -20.85mA
1.702V    -22.36mA   -20.93mA   -24.89mA
1.965V    -20.5mA    -18.41mA   -23.39mA
2.185V    -19.39mA   -11.29mA   -22.29mA
2.361V    -12.5mA    -8.438mA   -21.82mA
2.668V    -7.4mA     -6.748mA   -9.848mA
[Ramp]
R_load=50.000Ohm
dV/dt_r   444.420mV/117.000ps  422.039mV/140.000ps  478.740mV/100.500ps
dV/dt_f   444.420mV/118.500ps  422.039mV/143.000ps  478.740mV/101.500ps
[Rising waveform]
R_fixture=50.000Ohm
V_fixture=1.350
V_fixture_min=1.283
V_fixture_max=1.450
0s        558.7mV    546.7mV    592.6mV
39ps      568.7mV    544.6mV    620.9mV
68ps      619.2mV    542.8mV    761.6mV
135ps     974.2mV    539.4mV    1.203V
173ps     1.141V     542.1mV    1.306V
211ps     1.225V     556.8mV    1.352V
269ps     1.278V     659.5mV    1.379V
374ps     1.302V     1.078V     1.391V
441ps     1.306V     1.191V     1.393V
938ps     1.308V     1.25V      1.394V
[Rising waveform]
R_fixture=50.000Ohm
V_fixture=0
0s        -5.263mV   819.7uV    -4.884mV
48ps      -7.822mV   894.5uV    20.35mV
87ps      49.07mV    96.57uV    168.2mV
173ps     358.6mV    -8.328mV   549.3mV
230ps     528.5mV    -8.295mV   679.9mV
278ps     619mV      40.94mV    736.5mV
432ps     720.7mV    451mV      791.7mV
527ps     733.8mV    606.9mV    797.9mV
662ps     739.1mV    680.3mV    800.9mV
938ps     741.5mV    703mV      802mV
[Falling waveform]
R_fixture=50.000Ohm
V_fixture=1.350
V_fixture_min=1.283
V_fixture_max=1.450
0s        1.313V     1.25V      1.399V
48ps      1.317V     1.249V     1.385V
87ps      1.27V      1.25V      1.26V
183ps     939.2mV    1.263V     837.4mV
230ps     791.9mV    1.256V     723.4mV
278ps     694.2mV    1.202V     662.7mV
432ps     589.7mV    795.7mV    609.1mV
518ps     577.7mV    654.3mV    603.9mV
642ps     571.7mV    582.7mV    601mV
938ps     568.5mV    553.1mV    600mV
[Falling waveform]
R_fixture=50.000Ohm
V_fixture=0
0s        755.3mV    705mV      811mV
29ps      741.2mV    706.3mV    781.4mV
58ps      673.7mV    709.1mV    643.1mV
106ps     428.8mV    716.8mV    305.8mV
135ps     273.4mV    720.5mV    174.9mV
202ps     83.5mV     684.9mV    49.29mV
240ps     43.34mV    595.5mV    25.37mV
345ps     9.094mV    181.1mV    4.429mV
413ps     3.627mV    62.21mV    1.455mV
938ps     17uV       168.6uV    7.288uV
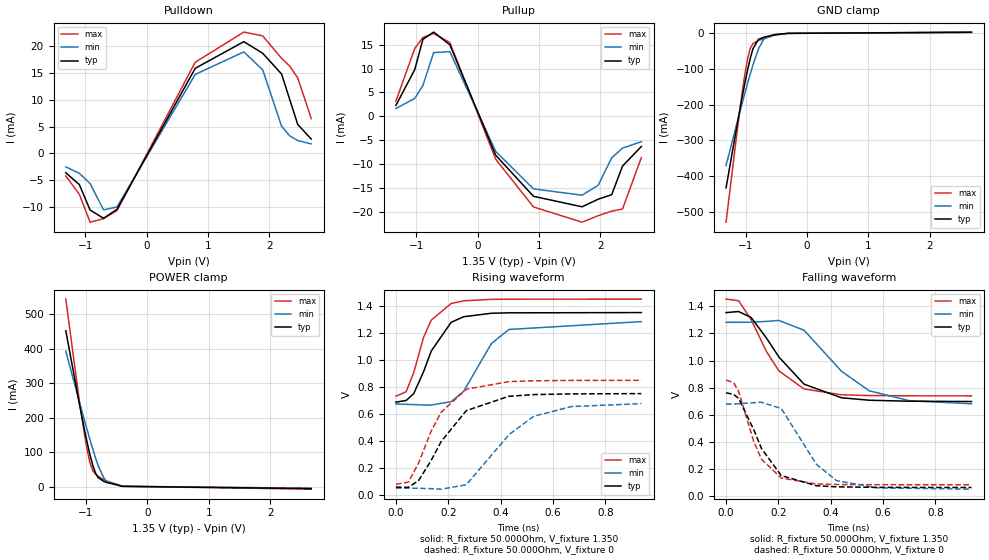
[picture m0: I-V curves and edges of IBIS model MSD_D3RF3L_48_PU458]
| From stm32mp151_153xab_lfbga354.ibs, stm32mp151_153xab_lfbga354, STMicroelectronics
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[Model] MSD_D3RF3L_48_PU458
Model_type   I/O
C_comp 2.396pF   2.311pF   2.520pF
Vinh = 810.000mV
Vinl = 540.000mV
Vmeas = 675.000mV
Vref = 675.000mV
[Model Spec]
Vinh   810.000mV   777.000mV   860.000mV
Vinl   540.000mV   507.000mV   590.000mV
Vmeas   675.000mV   642.000mV   725.000mV
Vref   675.000mV   642.000mV   725.000mV
[Temperature Range]   25.000   125.000   -40.000
[Voltage Range]   1.350V   1.283V   1.450V
[GND Clamp Reference]   0.00V   0.00V   0.00V
[Pulldown Reference]   0.00V   0.00V   0.00V
[POWER Clamp Reference]   1.350V   1.283V   1.450V
[Pullup Reference]   1.350V   1.283V   1.450V
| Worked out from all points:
|   slope of the pulldown table from 0 to 0.203 V, typ, clamps not added: 42.2 ohm
|   slope of the pullup table from 0 to 0.203 V, typ, clamps not added: 34.5 ohm
|   GND clamp passes 1 mA (typ) near -0.40 V on its own axis
|   POWER clamp passes 1 mA (typ) near -0.41 V on its own axis
|   rising waveform, R_fixture 50.000Ohm, V_fixture 1.350: 20-80 % time 91ps typ, 114ps min, 76ps max; typ from 0.687 V to 1.35 V
|   rising waveform, R_fixture 50.000Ohm, V_fixture 0: 20-80 % time 143ps typ, 174ps min, 120ps max; typ from 0.058 V to 0.75 V
|   falling waveform, R_fixture 50.000Ohm, V_fixture 1.350: 20-80 % time 161ps typ, 193ps min, 128ps max; typ from 1.35 V to 0.697 V
|   falling waveform, R_fixture 50.000Ohm, V_fixture 0: 20-80 % time 104ps typ, 123ps min, 85.8ps max; typ from 0.762 V to 0.062 V
[GND Clamp]
-1.318V   -433.3mA   -370.7mA   -529.5mA
-1.142V   -261mA     -253.1mA   -280.7mA
-1.055V   -178.6mA   -195.5mA   -165.6mA
-1.011V   -139.4mA   -167.5mA   -114.5mA
-966.7mV  -102.7mA   -139.9mA   -71.66mA
-922.7mV  -69.78mA   -113.4mA   -42.02mA
-878.8mV  -43.16mA   -88.12mA   -28.62mA
-790.9mV  -17.05mA   -44.03mA   -20.47mA
-703mV    -10.93mA   -16.1mA    -14.81mA
-527.3mV  -3.949mA   -3.336mA   -5.27mA
-307.6mV  -123uA     -180.2uA   -110uA
2.68V     2.885mA    2.451mA    3.413mA
[Power Clamp]
-1.33V    452.7mA    393.2mA    544.5mA
-1.111V   242.2mA    247.6mA    251.2mA
-1.023V   162.6mA    190.6mA    148.4mA
-978.8mV  125.5mA    162.7mA    103.9mA
-934.9mV  91.37mA    135.4mA    68.38mA
-890.9mV  62mA       109.1mA    46.75mA
-847mV    39.66mA    84.12mA    36.27mA
-803mV    26.32mA    61.3mA     30.18mA
-715.1mV  15.66mA    26.54mA    20.71mA
-671.2mV  12.44mA    16.45mA    16.56mA
-407.6mV  911.2uA    1.194mA    1.103mA
2.668V    -5.686mA   -4.559mA   -7.317mA
[Pulldown]
-1.318V   -3.6mA     -2.5mA     -4.2mA
-1.098V   -5.8mA     -3.7mA     -7.6mA
-922.7mV  -10.55mA   -5.6mA     -12.83mA
-703mV    -12.11mA   -10.54mA   -12.17mA
-483.3mV  -10.41mA   -9.972mA   -10.65mA
790.9mV   15.91mA    14.77mA    17.05mA
1.582V    20.88mA    18.97mA    22.67mA
1.889V    18.72mA    15.63mA    21.96mA
2.197V    14.84mA    5.1mA      17.78mA
2.329V    10.1mA     3.3mA      16.32mA
2.461V    5.4mA      2.4mA      14.1mA
2.68V     2.7mA      1.8mA      6.5mA
[Pullup]
-1.33V    2.3mA      1.652mA    3.207mA
-1.023V   9.8mA      3.762mA    14.22mA
-890.9mV  16.12mA    6.472mA    16.51mA
-715.1mV  17.64mA    13.35mA    17.35mA
-451.5mV  14.98mA    13.54mA    15.46mA
295.4mV   -8.125mA   -7.33mA    -8.964mA
910.6mV   -16.72mA   -15.17mA   -18.95mA
1.702V    -18.92mA   -16.49mA   -22.14mA
1.965V    -17.33mA   -14.42mA   -20.78mA
2.185V    -16.38mA   -8.671mA   -19.82mA
2.361V    -10.4mA    -6.643mA   -19.39mA
2.668V    -6.3mA     -5.3mA     -8.621mA
[Ramp]
R_load=50.000Ohm
dV/dt_r   402.438mV/117.000ps  370.626mV/145.500ps  443.259mV/98.000ps
dV/dt_f   402.408mV/132.500ps  370.596mV/160.500ps  443.259mV/107.500ps
[Rising waveform]
R_fixture=50.000Ohm
V_fixture=1.350
V_fixture_min=1.283
V_fixture_max=1.450
0s        686.6mV    673.2mV    731mV
39ps      699.1mV    670.7mV    763.6mV
68ps      749.6mV    668.5mV    905.8mV
106ps     913.9mV    666mV      1.168V
135ps     1.065V     665.4mV    1.294V
211ps     1.278V     690mV      1.417V
259ps     1.319V     767.1mV    1.437V
365ps     1.345V     1.121V     1.448V
432ps     1.348V     1.225V     1.449V
938ps     1.35V      1.283V     1.45V
[Rising waveform]
R_fixture=50.000Ohm
V_fixture=0
0s        57.55mV    49.91mV    78.34mV
48ps      55.99mV    49.84mV    95.06mV
87ps      107mV      49.05mV    237.6mV
135ps     256.2mV    46.18mV    473.8mV
173ps     395.4mV    42.4mV     612.8mV
269ps     624mV      74.85mV    782.2mV
432ps     730.3mV    446mV      838.9mV
527ps     742.7mV    582.6mV    844.7mV
671ps     747.8mV    654mV      847.7mV
938ps     750mV      675.6mV    848.3mV
[Falling waveform]
R_fixture=50.000Ohm
V_fixture=1.350
V_fixture_min=1.283
V_fixture_max=1.450
0s        1.354V     1.282V     1.454V
48ps      1.362V     1.282V     1.442V
96ps      1.318V     1.283V     1.302V
154ps     1.167V     1.289V     1.068V
202ps     1.026V     1.296V     923.4mV
298ps     825.5mV    1.224V     790.1mV
441ps     724.9mV    920.9mV    746.7mV
547ps     706.7mV    776.4mV    741.3mV
700ps     699.3mV    703.6mV    739.3mV
938ps     697.1mV    680.4mV    738.7mV
[Falling waveform]
R_fixture=50.000Ohm
V_fixture=0
0s        761.5mV    677.7mV    856mV
29ps      750mV      678.9mV    835.6mV
48ps      720.1mV    680.5mV    771.7mV
106ps     488.3mV    688.5mV    401.8mV
135ps     351.3mV    691.6mV    272.1mV
211ps     150.2mV    645.5mV    131.6mV
345ps     75mV       234.2mV    88.08mV
422ps     66.92mV    113mV      84.09mV
575ps     62.89mV    59.62mV    82.69mV
938ps     62.26mV    49.65mV    82.48mV
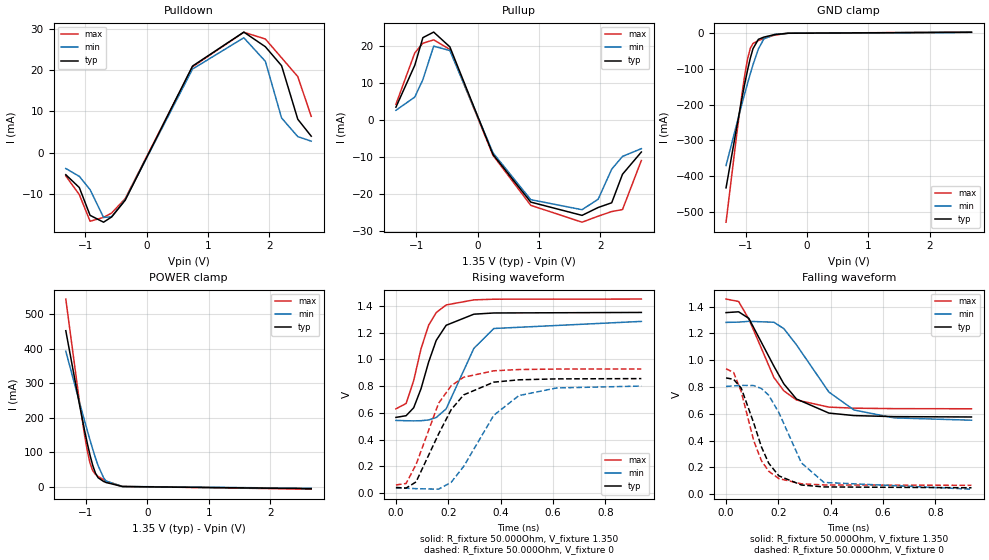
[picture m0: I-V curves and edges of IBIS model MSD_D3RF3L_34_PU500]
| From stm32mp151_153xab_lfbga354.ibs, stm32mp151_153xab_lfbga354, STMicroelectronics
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[Model] MSD_D3RF3L_34_PU500
Model_type   I/O
C_comp 2.412pF   2.328pF   2.536pF
Vinh = 810.000mV
Vinl = 540.000mV
Vmeas = 675.000mV
Vref = 675.000mV
[Model Spec]
Vinh   810.000mV   777.000mV   860.000mV
Vinl   540.000mV   507.000mV   590.000mV
Vmeas   675.000mV   642.000mV   725.000mV
Vref   675.000mV   642.000mV   725.000mV
[Temperature Range]   25.000   125.000   -40.000
[Voltage Range]   1.350V   1.283V   1.450V
[GND Clamp Reference]   0.00V   0.00V   0.00V
[Pulldown Reference]   0.00V   0.00V   0.00V
[POWER Clamp Reference]   1.350V   1.283V   1.450V
[Pullup Reference]   1.350V   1.283V   1.450V
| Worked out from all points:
|   slope of the pulldown table from 0 to 0.203 V, typ, clamps not added: 31 ohm
|   slope of the pullup table from 0 to 0.203 V, typ, clamps not added: 26.2 ohm
|   GND clamp passes 1 mA (typ) near -0.40 V on its own axis
|   POWER clamp passes 1 mA (typ) near -0.41 V on its own axis
|   rising waveform, R_fixture 50.000Ohm, V_fixture 1.350: 20-80 % time 81.6ps typ, 104ps min, 71.1ps max; typ from 0.566 V to 1.35 V
|   rising waveform, R_fixture 50.000Ohm, V_fixture 0: 20-80 % time 125ps typ, 150ps min, 109ps max; typ from 0.042 V to 0.855 V
|   falling waveform, R_fixture 50.000Ohm, V_fixture 1.350: 20-80 % time 134ps typ, 167ps min, 117ps max; typ from 1.35 V to 0.576 V
|   falling waveform, R_fixture 50.000Ohm, V_fixture 0: 20-80 % time 91.7ps typ, 112ps min, 79.9ps max; typ from 0.868 V to 0.048 V
[GND Clamp]
-1.318V   -433.4mA   -370.8mA   -529.6mA
-1.142V   -261.1mA   -253.1mA   -280.9mA
-1.055V   -178.7mA   -195.6mA   -165.8mA
-1.011V   -139.5mA   -167.5mA   -114.6mA
-966.7mV  -102.8mA   -140.1mA   -71.78mA
-922.7mV  -69.86mA   -113.4mA   -42.13mA
-878.8mV  -43.23mA   -88.18mA   -28.72mA
-790.9mV  -17.1mA    -44.08mA   -20.55mA
-703mV    -10.97mA   -16.13mA   -14.88mA
-527.3mV  -3.968mA   -3.356mA   -5.305mA
-307.6mV  -123.2uA   -182.6uA   -113.4uA
2.68V     2.644mA    2.247mA    3.128mA
[Power Clamp]
-1.33V    452.9mA    393.4mA    544.7mA
-1.111V   242.3mA    247.7mA    251.3mA
-1.023V   162.7mA    190.7mA    148.5mA
-978.8mV  125.6mA    162.8mA    103.9mA
-934.9mV  91.45mA    135.5mA    68.48mA
-890.9mV  62.07mA    109.1mA    46.85mA
-847mV    39.74mA    84.18mA    36.35mA
-803mV    26.37mA    61.36mA    30.26mA
-715.1mV  15.7mA     26.59mA    20.77mA
-671.2mV  12.49mA    16.49mA    16.61mA
-407.6mV  917.9uA    1.201mA    1.111mA
2.668V    -5.217mA   -4.179mA   -6.701mA
[Pulldown]
-1.318V   -5.3mA     -3.8mA     -5.6mA
-1.098V   -8.4mA     -5.7mA     -10.1mA
-922.7mV  -15.11mA   -8.9mA     -16.54mA
-703mV    -16.77mA   -15.62mA   -15.61mA
-571.2mV  -15.5mA    -15.46mA   -14.56mA
-351.5mV  -11.49mA   -11.33mA   -11.1mA
747mV     20.95mA    20.23mA    20.78mA
1.582V    29.15mA    27.78mA    29.11mA
1.933V    25.61mA    22.08mA    27.48mA
2.197V    21.03mA    8.4mA      22.94mA
2.461V    8.1mA      3.9mA      18.4mA
2.68V     4mA        2.8mA      8.8mA
[Pullup]
-1.33V    3.4mA      2.557mA    4.179mA
-1.023V   14.7mA     6.125mA    18.04mA
-890.9mV  22.16mA    10.83mA    20.65mA
-715.1mV  23.66mA    19.86mA    21.56mA
-451.5mV  19.67mA    18.67mA    18.99mA
251.5mV   -9.374mA   -8.927mA   -9.602mA
866.7mV   -22.22mA   -21.56mA   -23.09mA
1.702V    -25.8mA    -24.27mA   -27.64mA
1.965V    -23.67mA   -21.43mA   -26.01mA
2.185V    -22.4mA    -13.33mA   -24.77mA
2.361V    -14.7mA    -9.89mA    -24.23mA
2.668V    -8.7mA     -7.795mA   -10.98mA
[Ramp]
R_load=50.000Ohm
dV/dt_r   474.381mV/103.500ps  448.926mV/127.000ps  502.029mV/90.000ps
dV/dt_f   474.381mV/113.000ps  448.926mV/140.500ps  502.029mV/99.000ps
[Rising waveform]
R_fixture=50.000Ohm
V_fixture=1.350
V_fixture_min=1.283
V_fixture_max=1.450
0s        565.5mV    543.1mV    629.5mV
39ps      578.2mV    540.6mV    669.7mV
68ps      637.9mV    539.6mV    842mV
96ps      780.1mV    540.8mV    1.079V
125ps     979.2mV    546.5mV    1.255V
154ps     1.141V     564.8mV    1.349V
192ps     1.254V     629.2mV    1.406V
298ps     1.337V     1.082V     1.444V
374ps     1.346V     1.23V      1.449V
938ps     1.35V      1.283V     1.45V
[Rising waveform]
R_fixture=50.000Ohm
V_fixture=0
0s        41.93mV    37.96mV    60.57mV
39ps      37.19mV    36.36mV    71.7mV
77ps      83.35mV    32.87mV    213.4mV
163ps     441.4mV    29.08mV    670.9mV
211ps     623.1mV    80.04mV    802mV
259ps     733.8mV    199.5mV    865.8mV
374ps     828.9mV    581.3mV    913.8mV
470ps     846.5mV    728.7mV    923.3mV
614ps     853.4mV    785.6mV    926.8mV
938ps     855.4mV    799.6mV    927.3mV
[Falling waveform]
R_fixture=50.000Ohm
V_fixture=1.350
V_fixture_min=1.283
V_fixture_max=1.450
0s        1.355V     1.282V     1.456V
48ps      1.361V     1.284V     1.438V
87ps      1.312V     1.29V      1.307V
183ps     954.9mV    1.283V     870.3mV
221ps     822.9mV    1.235V     771.2mV
269ps     710.5mV    1.115V     703.4mV
393ps     605.4mV    762.4mV    649.9mV
489ps     586.7mV    628.5mV    642mV
642ps     579mV      569.5mV    638.5mV
938ps     576.2mV    552.2mV    637.5mV
[Falling waveform]
R_fixture=50.000Ohm
V_fixture=0
0s        867.9mV    804mV      936mV
29ps      857mV      808mV      908.1mV
58ps      791.9mV    812.4mV    765.2mV
106ps     530.2mV    810.5mV    397.3mV
135ps     354mV      788.9mV    251.4mV
163ps     231.6mV    738.8mV    171.3mV
202ps     136.8mV    608.1mV    116.5mV
288ps     68.74mV    234.1mV    77.79mV
374ps     54.44mV    87.84mV    69.2mV
938ps     48.15mV    37.72mV    66.47mV
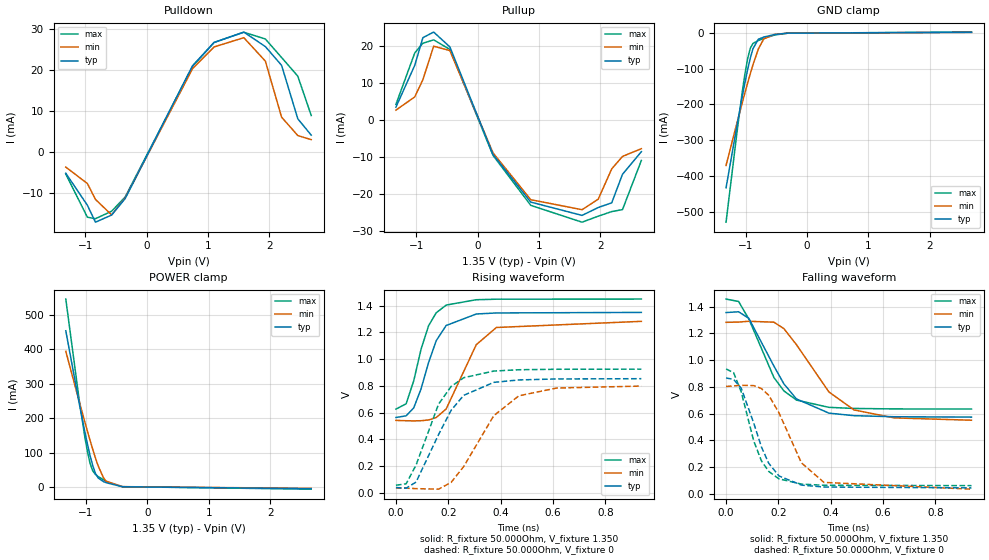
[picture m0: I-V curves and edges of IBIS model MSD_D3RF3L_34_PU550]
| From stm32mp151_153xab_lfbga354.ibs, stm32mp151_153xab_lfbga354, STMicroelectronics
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[Model] MSD_D3RF3L_34_PU550
Model_type   I/O
C_comp 2.425pF   2.340pF   2.550pF
Vinh = 810.000mV
Vinl = 540.000mV
Vmeas = 675.000mV
Vref = 675.000mV
[Model Spec]
Vinh   810.000mV   777.000mV   860.000mV
Vinl   540.000mV   507.000mV   590.000mV
Vmeas   675.000mV   642.000mV   725.000mV
Vref   675.000mV   642.000mV   725.000mV
[Temperature Range]   25.000   125.000   -40.000
[Voltage Range]   1.350V   1.283V   1.450V
[GND Clamp Reference]   0.00V   0.00V   0.00V
[Pulldown Reference]   0.00V   0.00V   0.00V
[POWER Clamp Reference]   1.350V   1.283V   1.450V
[Pullup Reference]   1.350V   1.283V   1.450V
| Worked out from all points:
|   slope of the pulldown table from 0 to 0.203 V, typ, clamps not added: 31 ohm
|   slope of the pullup table from 0 to 0.203 V, typ, clamps not added: 26.2 ohm
|   GND clamp passes 1 mA (typ) near -0.40 V on its own axis
|   POWER clamp passes 1 mA (typ) near -0.41 V on its own axis
|   rising waveform, R_fixture 50.000Ohm, V_fixture 1.350: 20-80 % time 82.1ps typ, 104ps min, 71.5ps max; typ from 0.563 V to 1.35 V
|   rising waveform, R_fixture 50.000Ohm, V_fixture 0: 20-80 % time 126ps typ, 151ps min, 110ps max; typ from 0.038 V to 0.853 V
|   falling waveform, R_fixture 50.000Ohm, V_fixture 1.350: 20-80 % time 135ps typ, 167ps min, 118ps max; typ from 1.35 V to 0.573 V
|   falling waveform, R_fixture 50.000Ohm, V_fixture 0: 20-80 % time 91.9ps typ, 113ps min, 80.2ps max; typ from 0.866 V to 0.044 V
[GND Clamp]
-1.318V   -433.6mA   -370.9mA   -529.9mA
-1.142V   -261.3mA   -253.2mA   -281mA
-1.055V   -178.7mA   -195.7mA   -165.9mA
-1.011V   -139.6mA   -167.6mA   -114.8mA
-966.7mV  -102.8mA   -140.1mA   -71.88mA
-922.7mV  -69.94mA   -113.6mA   -42.23mA
-878.8mV  -43.31mA   -88.24mA   -28.81mA
-790.9mV  -17.16mA   -44.13mA   -20.63mA
-703mV    -11.02mA   -16.16mA   -14.93mA
-527.3mV  -3.992mA   -3.373mA   -5.331mA
-307.6mV  -127.2uA   -185uA     -115.4uA
2.68V     2.404mA    2.042mA    2.844mA
[Power Clamp]
-1.33V    453mA      393.5mA    545mA
-1.111V   242.5mA    247.8mA    251.5mA
-1.023V   162.8mA    190.8mA    148.6mA
-978.8mV  125.6mA    162.8mA    104.1mA
-934.9mV  91.53mA    135.6mA    68.58mA
-890.9mV  62.14mA    109.2mA    46.94mA
-847mV    39.8mA     84.23mA    36.44mA
-803mV    26.44mA    61.41mA    30.34mA
-715.1mV  15.75mA    26.63mA    20.83mA
-671.2mV  12.52mA    16.53mA    16.67mA
-407.6mV  924.4uA    1.209mA    1.119mA
2.668V    -4.735mA   -3.8mA     -6.092mA
[Pulldown]
-1.318V   -5.3mA     -3.8mA     -5.5mA
-966.7mV  -13.1mA    -7.8mA     -16.02mA
-834.9mV  -17.24mA   -11.68mA   -16.39mA
-571.2mV  -15.49mA   -15.46mA   -14.56mA
-351.5mV  -11.49mA   -11.33mA   -11.1mA
747mV     20.95mA    20.23mA    20.78mA
1.098V    26.62mA    25.53mA    26.63mA
1.582V    29.15mA    27.78mA    29.11mA
1.933V    25.61mA    22.07mA    27.47mA
2.197V    21.04mA    8.4mA      22.95mA
2.461V    8mA        3.9mA      18.4mA
2.68V     4mA        2.9mA      8.8mA
[Pullup]
-1.33V    3.4mA      2.605mA    4.152mA
-1.023V   14.7mA     6.177mA    18.04mA
-890.9mV  22.16mA    10.81mA    20.65mA
-715.1mV  23.66mA    19.86mA    21.56mA
-451.5mV  19.67mA    18.67mA    18.99mA
251.5mV   -9.373mA   -8.925mA   -9.602mA
866.7mV   -22.21mA   -21.56mA   -23.09mA
1.702V    -25.8mA    -24.26mA   -27.63mA
1.965V    -23.67mA   -21.43mA   -26.01mA
2.185V    -22.41mA   -13.26mA   -24.77mA
2.361V    -14.7mA    -9.885mA   -24.23mA
2.668V    -8.6mA     -7.795mA   -10.98mA
[Ramp]
R_load=50.000Ohm
dV/dt_r   475.956mV/104.000ps  450.138mV/128.000ps  504.198mV/91.500ps
dV/dt_f   475.956mV/113.500ps  450.138mV/141.000ps  504.198mV/99.000ps
[Rising waveform]
R_fixture=50.000Ohm
V_fixture=1.350
V_fixture_min=1.283
V_fixture_max=1.450
0s        562.6mV    540.8mV    625.4mV
39ps      575.1mV    538.3mV    665.3mV
68ps      634.5mV    537.3mV    837.1mV
96ps      776.3mV    538.4mV    1.074V
125ps     975.5mV    544.2mV    1.251V
154ps     1.138V     562.3mV    1.347V
192ps     1.252V     626.5mV    1.405V
307ps     1.338V     1.108V     1.445V
384ps     1.346V     1.237V     1.449V
938ps     1.35V      1.283V     1.45V
[Rising waveform]
R_fixture=50.000Ohm
V_fixture=0
0s        37.69mV    34.65mV    54.75mV
39ps      32.85mV    33.06mV    65.7mV
77ps      78.75mV    29.55mV    206.5mV
163ps     435mV      25.58mV    662.7mV
211ps     616.8mV    76.26mV    795.3mV
259ps     728.6mV    195.1mV    860.8mV
374ps     825.8mV    576.3mV    910.6mV
470ps     844.1mV    725.2mV    920.4mV
614ps     851.3mV    783.4mV    924mV
938ps     853.4mV    798mV      924.6mV
[Falling waveform]
R_fixture=50.000Ohm
V_fixture=1.350
V_fixture_min=1.283
V_fixture_max=1.450
0s        1.355V     1.282V     1.456V
48ps      1.361V     1.284V     1.438V
87ps      1.312V     1.29V      1.307V
183ps     954.5mV    1.283V     869.1mV
221ps     822.1mV    1.235V     769.3mV
269ps     709.2mV    1.115V     700.8mV
393ps     603mV      761.6mV    646.2mV
489ps     584mV      626.9mV    638mV
642ps     576mV      567.4mV    634.5mV
938ps     573.2mV    549.9mV    633.4mV
[Falling waveform]
R_fixture=50.000Ohm
V_fixture=0
0s        866mV      802.4mV    933.4mV
29ps      855mV      806.5mV    905.2mV
58ps      789.6mV    810.8mV    761.8mV
106ps     527.3mV    808.9mV    393.4mV
135ps     350.9mV    787.2mV    247.4mV
163ps     228.5mV    737mV      167mV
202ps     133.5mV    605.9mV    111.8mV
288ps     64.94mV    231.5mV    72.31mV
374ps     50.34mV    85.03mV    63.47mV
938ps     43.89mV    34.37mV    60.65mV
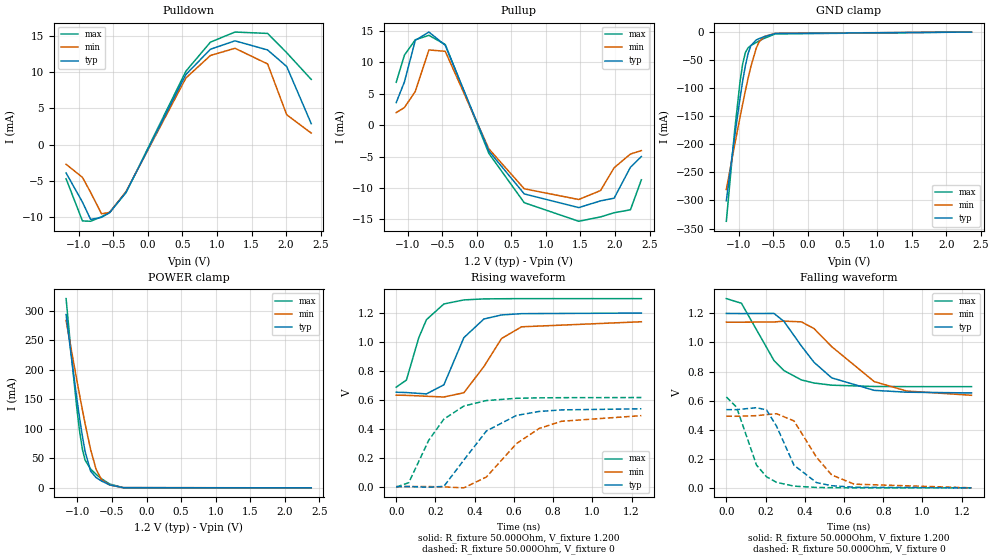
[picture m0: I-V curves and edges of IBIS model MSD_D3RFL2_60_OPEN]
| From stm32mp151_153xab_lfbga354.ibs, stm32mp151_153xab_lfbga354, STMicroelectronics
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[Model] MSD_D3RFL2_60_OPEN
Model_type   I/O
C_comp 2.581pF   2.493pF   2.708pF
Vinh = 820.000mV
Vinl = 380.000mV
Vmeas = 600.000mV
Vref = 600.000mV
[Model Spec]
Vinh   820.000mV   790.000mV   870.000mV
Vinl   380.000mV   350.000mV   430.000mV
Vmeas   600.000mV   570.000mV   650.000mV
Vref   600.000mV   570.000mV   650.000mV
[Temperature Range]   25.000   125.000   -40.000
[Voltage Range]   1.200V   1.140V   1.300V
[GND Clamp Reference]   0.00V   0.00V   0.00V
[Pulldown Reference]   0.00V   0.00V   0.00V
[POWER Clamp Reference]   1.200V   1.140V   1.300V
[Pullup Reference]   1.200V   1.140V   1.300V
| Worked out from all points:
|   slope of the pulldown table from 0 to 0.18 V, typ, clamps not added: 50.1 ohm
|   slope of the pullup table from 0 to 0.18 V, typ, clamps not added: 42.9 ohm
|   GND clamp passes 1 mA (typ) near -0.40 V on its own axis
|   POWER clamp passes 1 mA (typ) near -0.41 V on its own axis
|   rising waveform, R_fixture 50.000Ohm, V_fixture 1.200: 20-80 % time 113ps typ, 141ps min, 94.2ps max; typ from 0.653 V to 1.2 V
|   rising waveform, R_fixture 50.000Ohm, V_fixture 0: 20-80 % time 194ps typ, 233ps min, 165ps max; typ from 0 V to 0.538 V
|   falling waveform, R_fixture 50.000Ohm, V_fixture 1.200: 20-80 % time 206ps typ, 254ps min, 170ps max; typ from 1.2 V to 0.653 V
|   falling waveform, R_fixture 50.000Ohm, V_fixture 0: 20-80 % time 120ps typ, 146ps min, 104ps max; typ from 0.538 V to 0 V
[GND Clamp]
-1.182V   -300.5mA   -280.4mA   -337mA
-1.064V   -188.1mA   -202.5mA   -178.5mA
-984.9mV  -118.6mA   -152.2mA   -89.49mA
-945.5mV  -87.16mA   -127.9mA   -56.6mA
-906.1mV  -59.71mA   -104.4mA   -36.4mA
-866.7mV  -38.14mA   -82.14mA   -27.92mA
-827.3mV  -24.29mA   -61.54mA   -24.05mA
-748.5mV  -14mA      -28.45mA   -18.47mA
-709.1mV  -11.76mA   -17.8mA    -15.89mA
-630.3mV  -8.132mA   -7.75mA    -11.05mA
-472.7mV  -2.557mA   -2.242mA   -3.323mA
2.364V    29.58nA    484.6nA    2.864nA
[Power Clamp]
-1.164V   293.6mA    283.6mA    320.6mA
-1.085V   219.6mA    231.9mA    221.3mA
-1.006V   149.3mA    180.9mA    132.2mA
-966.7mV  116.7mA    156mA      94.33mA
-927.3mV  86.87mA    131.6mA    64.9mA
-887.9mV  61.07mA    108mA      46.71mA
-809.1mV  28.38mA    64.84mA    31.83mA
-730.3mV  17.49mA    31.58mA    22.97mA
-651.5mV  11.58mA    13.7mA     15.38mA
-533.3mV  4.956mA    4.897mA    6.46mA
-336.4mV  215.7uA    403.7uA    242.8uA
2.382V    -24.83nA   -515.5nA   -2.721nA
[Pulldown]
-1.182V   -3.9mA     -2.7mA     -4.7mA
-945.5mV  -7.91mA    -4.5mA     -10.51mA
-827.3mV  -10.3mA    -6.57mA    -10.56mA
-669.7mV  -10.02mA   -9.53mA    -9.95mA
-551.5mV  -9.376mA   -9.339mA   -9.297mA
-315.1mV  -6.567mA   -6.464mA   -6.607mA
551.5mV   9.679mA    9.198mA    10.14mA
906.1mV   13.16mA    12.3mA     14.14mA
1.261V    14.32mA    13.29mA    15.53mA
1.733V    13.06mA    11.13mA    15.34mA
2.009V    10.78mA    4.13mA     12.68mA
2.364V    2.9mA      1.6mA      9mA
[Pullup]
-1.164V   3.6mA      2.005mA    6.838mA
-1.045V   6.9mA      2.809mA    11.16mA
-887.9mV  13.52mA    5.386mA    13.61mA
-690.9mV  14.84mA    11.99mA    14.32mA
-454.5mV  12.73mA    11.77mA    12.85mA
175.8mV   -4.107mA   -3.772mA   -4.491mA
687.9mV   -10.95mA   -10.13mA   -12.35mA
1.476V    -13.13mA   -11.84mA   -15.31mA
1.791V    -12.06mA   -10.42mA   -14.62mA
1.988V    -11.63mA   -6.784mA   -13.95mA
2.224V    -6.7mA     -4.595mA   -13.48mA
2.382V    -5mA       -4.048mA   -8.7mA
[Ramp]
R_load=50.000Ohm
dV/dt_r   325.740mV/154.000ps  300.119mV/189.000ps  366.030mV/129.500ps
dV/dt_f   325.740mV/164.000ps  300.090mV/202.500ps  366.060mV/137.500ps
[Rising waveform]
R_fixture=50.000Ohm
V_fixture=1.200
V_fixture_min=1.140
V_fixture_max=1.300
0s        652.7mV    632.6mV    687.5mV
52ps      650.6mV    631.1mV    736.9mV
115ps     644.6mV    627.6mV    1.029V
154ps     641.2mV    624.8mV    1.154V
243ps     703.8mV    619.8mV    1.263V
345ps     1.03V      649.1mV    1.291V
447ps     1.159V     829.9mV    1.298V
537ps     1.187V     1.024V     1.299V
639ps     1.196V     1.105V     1.3V
1.25ns    1.2V       1.14V      1.3V
[Rising waveform]
R_fixture=50.000Ohm
V_fixture=0
0s        161.8uV    145.7uV    -3.34mV
64ps      664.3uV    500.1uV    27.44mV
166ps     -3.824mV   537.3uV    321.1mV
243ps     1.664mV    -1.949mV   466.7mV
345ps     184.1mV    -8.286mV   557.3mV
460ps     385mV      66.6mV     595.2mV
613ps     492.1mV    297.1mV    610.8mV
728ps     519.7mV    401.8mV    613.9mV
843ps     530.6mV    452mV      615mV
1.25ns    538.2mV    490.8mV    616mV
[Falling waveform]
R_fixture=50.000Ohm
V_fixture=1.200
V_fixture_min=1.140
V_fixture_max=1.300
0s        1.2V       1.14V      1.302V
77ps      1.199V     1.14V      1.27V
243ps     1.2V       1.141V     875.9mV
294ps     1.145V     1.147V     806.6mV
383ps     975.4mV    1.142V     742.3mV
447ps     864mV      1.096V     721.3mV
537ps     756.8mV    971.8mV    706.3mV
754ps     670.7mV    731.1mV    697.4mV
920ps     658mV      666mV      696.5mV
1.25ns    653mV      636.8mV    696.2mV
[Falling waveform]
R_fixture=50.000Ohm
V_fixture=0
0s        538.1mV    492.8mV    625.2mV
52ps      537.9mV    492.4mV    555mV
154ps     551.4mV    496.6mV    156.2mV
205ps     535.9mV    503.8mV    75.99mV
256ps     424.3mV    510mV      37.94mV
345ps     155.6mV    460.5mV    11.69mV
460ps     36.05mV    210.1mV    2.624mV
537ps     14.72mV    88.74mV    935.2uV
652ps     3.929mV    25.24mV    273.8uV
1.25ns    21.37uV    48.16uV    -8.003uV
